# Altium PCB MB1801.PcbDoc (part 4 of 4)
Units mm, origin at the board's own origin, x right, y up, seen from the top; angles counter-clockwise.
Board outline 70.1 x 57.1 mm, 4 copper layers (Top Layer, Signal Layer 1, Signal Layer 2, Bottom Layer), stack 1.614 mm thick; 219 components, 166 nets, 1002 pads, 473 vias.
Unrouted connection lines stored in the file: 2.

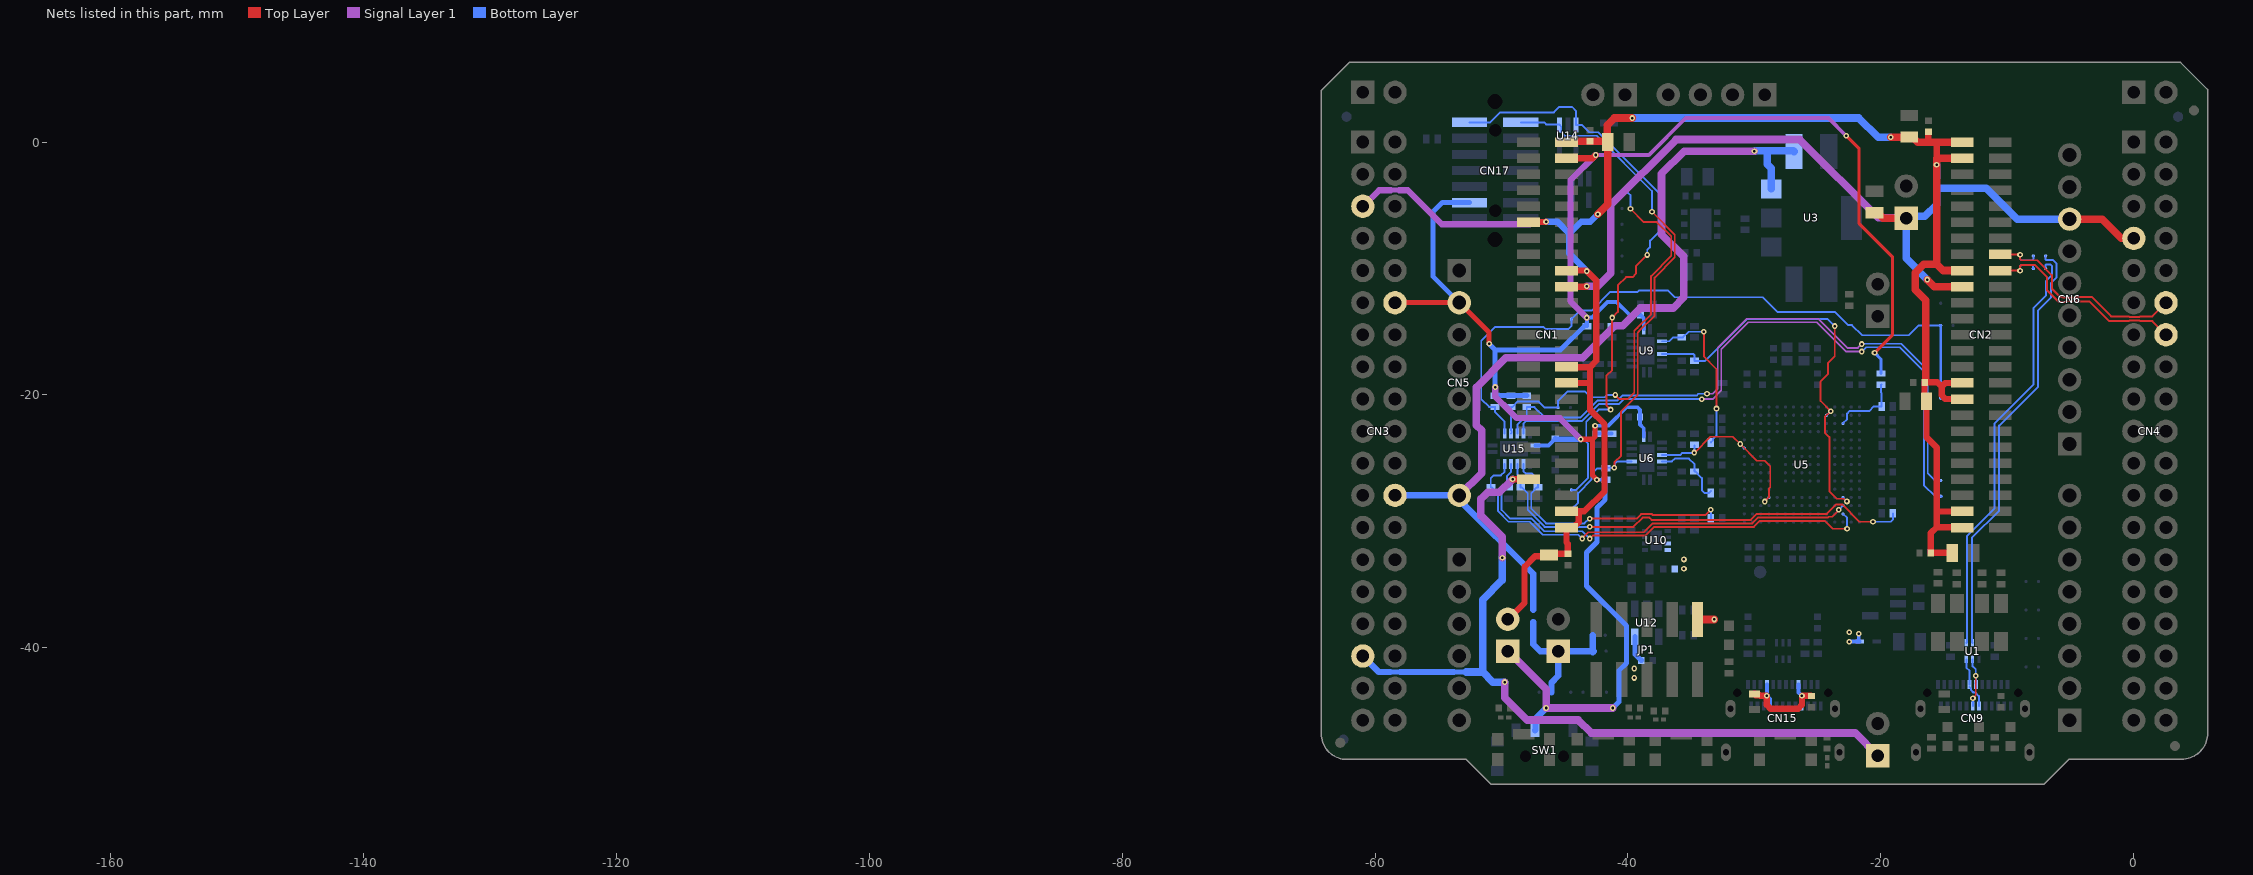
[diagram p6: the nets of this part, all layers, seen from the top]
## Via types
v1: diameter 0.45, hole 0.2, Top Layer to Bottom Layer, tented both sides, 473 vias

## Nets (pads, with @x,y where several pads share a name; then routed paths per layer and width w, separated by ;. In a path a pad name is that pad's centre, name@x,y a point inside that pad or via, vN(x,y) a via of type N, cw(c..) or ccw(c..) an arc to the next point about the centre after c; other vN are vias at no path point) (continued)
T_SWDIO: R26.1 U5.L2 U5.N12 U9.5 | length 32.6
  Top Layer w0.15: -24.1,-23.325 -24.425,-23 -24.425,-21.725 v1(-23.975,-21.275) -24.775,-20.475 -24.775,-18.925 -24.175,-18.325 -24.175,-17.45 -23.65,-16.925 v1(-23.65,-14.55) ; -24.075,-23.325 -24.075,-27.626 -23.501,-28.2 -22.921,-28.2 -22.705,-28.416 v1(-22.683,-28.416)
  Bottom Layer w0.15: U9.5@-37.3,-16.75 -34.85,-16.75 -34.75,-16.85 R26.1@-34.75,-17.3 -33.889,-17.3 -30.589,-14 -24.2,-14 v1(-23.65,-14.55) ; U5.L2@-24.3,-21.6 v1(-23.975,-21.275) ; U5.N12@-23,-28.1 v1(-22.683,-28.416)
T_SWO: R15.1 U5.A6 U5.D12 U6.4 | length 14.6
  Top Layer w0.15: v1(-34.75,-24.55) -34.725,-24.55 -33.475,-23.3 -31.7,-23.3 v1(-31.125,-23.875) -29.8,-25.2 -29.199,-25.2 -28.825,-25.574 ; v1(-29.175,-28.425) -28.85,-28.1 -28.85,-27.401 -28.825,-27.376 -28.75,-27.301 -28.75,-25.649 -28.825,-25.574
  Bottom Layer w0.15: U6.4@-37.3,-24.75 -35.875,-24.75 -35.7,-24.575 -34.75,-24.575 -34.75,-24.025 R15.1@-34.725,-24 ; v1(-31.125,-23.875) U5.A6@-30.8,-24.2 ; v1(-29.175,-28.425) U5.D12@-28.85,-28.1
T_VCC_AIN: R31.1 R33.1 U5.N3 | length 5.6
  Bottom Layer w0.15: U5.N3@-23,-22.25 -22.675,-21.925 -22.675,-21.467 -22.485,-21.277 -20.927,-21.277 -20.55,-20.9 R31.1@-20,-20.9 ; R31.1@-19.95,-20.9 -19.95,-19.928 -19.953,-19.925 -19.953,-19.847 -20,-19.8 R33.1@-20,-19.2 R33.1@-19.95,-19.15
T_VCP1_RX: R16.1 R55.2 U6.5 | length 6
  Bottom Layer w0.15: U6.5@-37.3,-25.25 -36.525,-25.25 -36.3,-25.025 -35.175,-25.025 -34.75,-25.45 -34.75,-25.5 -34.75,-25.925 R16.1@-34.775,-25.95 ; R16.1@-34.75,-26.05 -34.655,-26.05 -34.475,-26.23 -34.475,-26.25 -34.15,-26.575 -34.15,-27.525 -33.925,-27.75 -33.605,-27.75 R55.2@-33.45,-27.595
T_VCP1_TX: R24.2 R56.2 U9.3 | length 13
  Top Layer w0.15: v1(-34,-15) -34,-16.95 -33,-17.95 v1(-33,-21.075)
  Bottom Layer w0.15: U9.3@-37.3,-15.75 -36.725,-15.75 -36.425,-15.45 -35.655,-15.45 -35.205,-15 v1(-34,-15) ; R56.2@-33.45,-23.75 -33.27,-23.57 -33.27,-23.47 -33,-23.2 v1(-33,-21.075)
T_VCP2_CTS: R63.1 U5.N14 U15.5 | length 34.3
  Top Layer w0.15: v1(-43.025,-31.35) -43.012,-31.35 -42.787,-31.125 -38.636,-31.125 -37.936,-30.425 -30.047,-30.425 -29.572,-29.95 -24.425,-29.95 -23.8,-30.575 v1(-22.675,-30.575)
  Bottom Layer w0.15: R63.1@-49.595,-27.3 -49.775,-27.48 -50,-27.705 -50,-29.082 -49.332,-29.75 -47.653,-29.75 -46.628,-30.775 -43.6,-30.775 v1(-43.025,-31.35) ; R63.1@-49.57,-27.23 -49.57,-26.42 -49.25,-26.1 U15.5@-49.25,-25.45 ; U5.N14@-23,-29.4 -22.675,-29.725 v1(-22.675,-30.575)
T_VCP2_RTS: R64.1 U5.N13 U15.6 | length 34.1
  Top Layer w0.15: v1(-43.626,-31.351) -43.626,-31.337 -43.139,-30.85 -38.75,-30.85 -38.05,-30.15 -30.161,-30.15 -29.686,-29.675 -24.161,-29.675 -24.111,-29.625 -23.861,-29.625 v1@-23.305,-29.069
  Bottom Layer w0.15: U15.6@-49.75,-25.45 -49.75,-26.05 -50.05,-26.35 -50.6,-26.35 -50.85,-26.6 -50.85,-27.3 R64.1@-50.825,-27.3 -50.755,-27.3 -50.275,-27.78 -50.275,-29.196 -49.446,-30.025 -47.767,-30.025 -46.742,-31.05 -43.925,-31.05 v1(-43.626,-31.351) ; v1@-23.305,-29.069 -23.305,-29.055 U5.N13@-23,-28.75
  other v1: -23.325,-29.075
T_VCP2_RX: R57.2 R62.1 U15.4 | length 35.5
  Top Layer w0.15: v1(-43.025,-30.425) -39.575,-30.425 -38.849,-29.699 -38.3,-29.699 -38.124,-29.875 -30.275,-29.875 -29.8,-29.4 -24.275,-29.4 -23.525,-28.65 -23.075,-28.65 -21.7,-30.025 v1(-20.625,-30.025)
  Bottom Layer w0.15: U15.4@-48.75,-25.45 -48.75,-26.325 -48.5,-26.575 -48.5,-27.3 -48.38,-27.3 -48.2,-27.48 -48.2,-27.505 -47.925,-27.78 -47.925,-29.089 -46.589,-30.425 v1(-43.025,-30.425) ; v1(-20.625,-30.025) -19.225,-30.025 -19.05,-29.85 R57.2@-19.05,-29.35
T_VCP2_TX: R58.2 R61.1 U15.3 | length 20.4
  Top Layer w0.15: v1(-43.025,-29.775) -39.314,-29.775 -38.963,-29.424 -38.101,-29.424 -38.025,-29.5 -33.875,-29.5 v1(-33.45,-29.075)
  Bottom Layer w0.15: U15.3@-48.25,-25.45 -48.25,-26.05 -48.1,-26.2 -47.6,-26.2 -47.1,-26.7 R61.1@-47.1,-27.3 -47.195,-27.3 -47.65,-27.755 -47.65,-28.975 -46.475,-30.15 -43.438,-30.15 -43.063,-29.775 v1(-43.025,-29.775) ; R58.2@-33.45,-29.75 v1(-33.45,-29.075)
USB_C_N: CN9.A7 CN9.B7 U1.6 | length 4
  Bottom Layer w0.155: U1.6@-13.25,-40.9 -13.25,-41.55 -12.99,-41.81 CN9.A7@-12.99,-42.89 ; CN9.A7@-13,-43.08 -12.868,-43.212 -12.868,-43.334 -12.679,-43.522 -12.538,-43.522 -12.252,-43.808 -12.252,-44.578 CN9.B7@-12.24,-44.59
USB_C_P: CN9.A6 CN9.B6 U1.5 | length 4.5
  Top Layer w0.155: v1(-12.725,-43.975) -12.725,-43.962 -12.5,-43.737 v1(-12.5,-42.2)
  Bottom Layer w0.155: U1.5@-12.75,-40.9 -12.75,-41.45 -12.5,-41.7 v1(-12.5,-42.2) -12.495,-42.205 -12.495,-42.77 CN9.A6@-12.525,-42.8 ; CN9.B6@-12.74,-44.59 -12.732,-44.583 -12.732,-43.982 v1(-12.725,-43.975)
USB_FS_N: CN2.18 CN4.14 SB14.1 | length 18.1
  Top Layer w0.155: CN2.18@-10.565,-10.16 v1@-9,-10.16 ; v1(-9,-10.175) v1@-9,-10.16 ; CN4.14@2.54,-15.24 1.46,-14.16 0.515,-14.16 0.467,-14.112 -0.356,-14.112 -0.405,-14.16 -1.953,-14.16 -3.489,-12.625 -4.615,-12.625 -4.652,-12.588 -5.4,-12.588 -5.448,-12.636 -5.958,-12.636 -6.856,-11.738 -6.856,-10.683 -7.811,-9.728 -8.553,-9.728 -8.909,-9.728 -9,-9.819 v1@-9,-10.16
  Bottom Layer w0.155: v1(-9,-10.175) -9,-9.819 -8.909,-9.728 -8.042,-9.728 -7.967,-9.803 -7.967,-9.983 SB14.1@-7.95,-10
USB_FS_P: CN2.16 CN4.12 SB16.1 | length 18.2
  Top Layer w0.155: CN2.16@-10.565,-8.89 v1@-9,-8.89 ; v1(-9,-8.9) -9,-9.256 -8.909,-9.347 -8.711,-9.347 -7.653,-9.347 -6.475,-10.525 -6.475,-11.581 -5.8,-12.255 -5.627,-12.255 -5.579,-12.304 -4.675,-12.304 -4.615,-12.244 -3.331,-12.244 -1.795,-13.779 -0.405,-13.779 -0.356,-13.828 0.467,-13.828 0.515,-13.779 1.46,-13.779 CN4.12@2.54,-12.7
  Bottom Layer w0.155: v1(-9,-8.9) -9,-9.256 -8.909,-9.347 -8.041,-9.347 -7.95,-9.256 SB16.1@-7.95,-9
USB_N: SB14.2 U1.1 | length 33.5
  Bottom Layer w0.155: U1.1@-13.25,-39.6 -13.203,-39.552 -13.203,-39.299 -13.191,-39.287 -13.191,-31.141 -11.031,-28.981 -11.031,-22.256 -7.95,-19.175 -7.95,-13.144 -6.931,-12.125 -6.931,-10.981 -6.482,-10.532 -6.482,-9.781 -6.572,-9.691 -6.958,-9.691 -6.975,-9.708 SB14.2@-6.975,-10
USB_P: SB16.2 U1.2 | length 34.1
  Bottom Layer w0.155: U1.2@-12.75,-39.6 -12.798,-39.552 -12.798,-39.299 -12.81,-39.287 -12.81,-31.298 -10.65,-29.139 -10.65,-22.414 -7.569,-19.333 -7.569,-13.302 -6.55,-12.283 -6.55,-11.139 -6.101,-10.689 -6.101,-9.623 -6.415,-9.31 -6.958,-9.31 -6.975,-9.292 SB16.2@-6.975,-9
V_TARGET: C25.1 C31.1 C61.1 CN1.4 CN3.12 CN5.2 CN17.3 JP2.1 R18.2 R19.2 R28.2 R33.2 R60.2 R65.2 R66.2 R67.2 SB18.2 SW1.2 U6.16 U9.16 U15.16 | length 162
  Top Layer w0.25: v1(-22.75,0.5) -21.725,-0.525 -21.725,-6.45 -19.075,-9.1 -19.075,-15.225 v1(-20.5,-16.65)
  Top Layer w0.4: CN3.12@-58.42,-12.7 CN5.2@-53.34,-12.7 ; CN5.2@-53.25,-12.775 -50.975,-15.05 v1@-50.975,-15.936 ; v1(-43.725,-23.5) -42.8,-23.5 ; v1@-42.599,-22.439 -42.599,-23.299 -42.8,-23.5 ; v1(-42.45,-26.7) -42.8,-26.35 -42.8,-23.5
  Top Layer w0.5: CN1.4@-44.855,-1.27 -42.795,-1.27 v1(-42.55,-1.025)
  Signal Layer 1 w0.3: v1(-42.55,-1.025) -38.35,-1.025 -35.425,1.9 -24.15,1.9 v1(-22.75,0.5)
  Signal Layer 1 w0.5: v1(-50.5,-19.375) -50.5,-20.125 -49.9,-20.725 ; -49.875,-20.75 -48.8,-21.825 -45.4,-21.825 v1(-43.725,-23.5) ; v1@-43.263,-13.887 -44.55,-12.6 -44.55,-3.025 v1(-42.55,-1.025)
  Signal Layer 1 w0.6: JP2.1@-49.475,-40.275 -46.475,-43.275 v1(-46.475,-44.75) ; v1@-46.45,-44.725 -46.425,-44.75 v1(-41.2,-44.75)
  Bottom Layer w0.25: v1(-20.5,-16.65) -20,-17.15 R33.2@-20,-18.3
  Bottom Layer w0.3: U15.16@-47.3,-24 -46.275,-24 C61.1@-45.88,-23.605 ; R28.2@-43.25,-14.55 v1(-43.25,-13.875) -42.85,-13.875 -41.625,-12.65 -40.9,-12.65 -39.85,-13.7 C31.1@-39,-13.7 ; R18.2@-42.475,-23.025 -42.491,-23.025 -42.571,-22.945 -42.571,-22.454 -42.6,-22.425 -41.55,-22.425 -40.1,-20.975 -39.25,-20.975 -39.05,-21.175 C25.1@-39.05,-21.75 -39.05,-22.325 -38.75,-22.625 U6.16@-38.75,-23.3 ; v1(-42.45,-26.7) R19.2@-41.8,-26.7 ; R18.2@-42.45,-23.05 R60.2@-41.275,-23.05 ; C31.1@-39,-13.675 -38.75,-13.925 U9.16@-38.75,-14.8
  Bottom Layer w0.4: CN5.2@-53.34,-12.7 -55.4,-10.64 -55.4,-5.5 -54.675,-4.775 -52.547,-4.775 CN17.3@-52.532,-4.79 ; v1(-50.975,-15.95) -50.975,-15.964 -50.915,-16.024 -50.915,-16.035 -50.5,-16.45 ; R65.2@-48,-20.05 R66.2@-49.25,-20.05 R67.2@-50.5,-20.05 v1(-50.5,-19.375) -50.5,-16.45 ; C61.1@-45.75,-23.45 -45.7,-23.5 v1(-43.725,-23.5) ; R28.2@-43.375,-14.475 -45.35,-16.45 -50.5,-16.45 ; R19.2@-41.8,-26.7 -41.8,-28.275 -42.45,-28.925 -42.45,-31.625 -43.275,-32.45 -43.275,-35.1 -40.125,-38.25 -40.125,-41.2 -40.725,-41.8 SB18.2@-40.725,-43.5 ; v1(-41.2,-44.75) -40.725,-44.275 SB18.2@-40.725,-43.525
  Bottom Layer w0.5: SW1.2@-47.35,-46.509 -47.311,-46.471 -47.311,-45.586 v1(-46.475,-44.75)
  other v1: -42.599,-22.426
VBAT: CN1.43 CN3.33 CN14.1 | length 64.1
  Top Layer w0.5: v1(-49.125,-26.65) -47.875,-26.65 CN1.43@-47.855,-26.67
  Signal Layer 1 w0.6: v1(-49.925,-32.875) -49.925,-31.225 -51.625,-29.525 -51.625,-28.225 -51.1,-27.7 -50.175,-27.7 v1(-49.125,-26.65) ; v1(-49.75,-42.7) -49.75,-43.925 -47.975,-45.7 -43.925,-45.7 -42.9,-46.725 -22.045,-46.725 CN14.1@-20.25,-48.52
  Bottom Layer w0.4: -58.775,-41.9 -58.025,-41.9 ; -53.75,-41.9 -52.775,-41.9
  Bottom Layer w0.5: CN3.33@-60.96,-40.64 -59.7,-41.9 -58.775,-41.9 ; -58.025,-41.9 -57.125,-41.9 ; -57.1,-41.9 -53.75,-41.9
  Bottom Layer w0.6: -52.775,-41.9 -51.475,-41.9 ; v1(-49.925,-32.875) -49.925,-34.625 -51.475,-36.175 -51.475,-41.9 ; v1(-49.75,-42.7) -50.675,-42.7 -51.475,-41.9
VBUS_STLK: C23.1 C35.2 C58.2 CN15.A4 CN15.A9 CN15.B4 CN15.B9 D1.1 JP1.10 U7.1 U10.3 U10.4 U12.5 | length 14.7
  Top Layer w0.5: U7.1@-30.02,-43.625 -29.895,-43.75 -29.56,-43.75 -29.535,-43.775 v1(-29.02,-43.775) -29.02,-44.507 -28.727,-44.8 -26.538,-44.8 -26.245,-44.507 v1@-26.245,-43.8 ; v1(-26.245,-43.775) C23.1@-25.554,-43.775
  Top Layer w0.6: JP1.10@-34.5,-37.75 v1(-33.175,-37.75)
  Bottom Layer w0.3: CN15.A9@-29.01,-42.89 -29.01,-43.765 v1(-29.02,-43.775) -29.011,-43.775 -28.76,-44.026 CN15.B4@-28.76,-44.59 ; CN15.A4@-26.51,-42.89 -26.51,-43.522 -26.257,-43.775 v1(-26.245,-43.775) -26.26,-43.79 CN15.B9@-26.26,-44.59 ; v1(-22.5,-39.5) D1.1@-21.75,-39.5 ; v1(-21.75,-38.875) D1.1@-21.75,-39.5 ; D1.1@-21.675,-39.5 D1.1@-21.75,-39.5
  Bottom Layer w0.4: U12.5@-39.45,-39.1 -39.45,-40.5 -39.03,-40.92 -39.005,-40.92 -38.95,-40.975 C58.2@-38.95,-41
  other v1: -39.5,-42.375 -39.5,-41.625 -22.5,-38.75 -35.575,-33.75 -35.575,-33
VCP1_T_RX: CN17.13 R32.2 SB5.2 U14.3 | length 47.5
  Top Layer w0.15: v1(-41.376,-21.15) -41.7,-20.826 -41.7,-18.475 -41.25,-18.025 v1(-41.25,-13.875) -40.8,-13.425 -40.8,-11.325 -40.15,-10.675 -39.639,-10.675 -39.375,-10.411 -39.375,-9.828 v1@-38.475,-8.928
  Bottom Layer w0.15: CN17.13@-52.532,1.56 -50.89,1.56 -50.1,2.35 -45.85,2.35 -45.425,2.775 -44.425,2.775 -44.1,2.45 U14.3@-44.1,1.35 -43.65,1.35 -43.075,0.775 -42.361,0.775 -37.525,-4.061 -37.525,-7.075 -38.25,-7.8 -38.25,-8.3 -38.274,-8.324 -38.274,-8.326 -38.475,-8.528 v1(-38.475,-8.925) -38.469,-8.919 v1@-38.469,-8.9 ; SB5.2@-44.475,-27.5 -44.1,-27.5 -43.15,-26.55 -43.15,-23.85 -43.3,-23.7 -43.3,-22.125 -42.325,-21.15 v1(-41.376,-21.15) ; R32.2@-41.25,-14.55 v1(-41.25,-13.875)
VCP1_T_TX: CN17.14 R19.1 SB3.2 U6.12 U14.1 | length 44.9
  Top Layer w0.15: v1(-41.075,-25.75) -41.075,-25.325 -40.55,-24.8 -40.55,-21.3 -39.225,-19.975 -39.225,-15.063 -39.137,-14.975 ; -39.136,-14.975 -37.9,-13.739 -37.9,-10.715 -36.3,-9.115 -36.3,-8.903 -36.3,-7.325 -38.1,-5.525 v1(-38.1,-5.5)
  Bottom Layer w0.15: CN17.14@-48.468,1.56 -46.635,1.56 -46.475,1.4 -45.45,1.4 U14.1@-45.4,1.35 -45.275,1.225 -45.275,0.775 -45,0.5 -42.475,0.5 -38.1,-3.875 v1(-38.1,-5.5) ; SB3.2@-44.475,-29.25 -44.475,-29.05 -43.95,-28.525 -43.95,-27.75 -42.875,-26.675 -42.875,-26.25 -42.425,-25.8 R19.1@-41.75,-25.8 -41.7,-25.75 v1(-41.075,-25.75) -41.032,-25.707 -41.032,-25.432 -40.85,-25.25 U6.12@-39.7,-25.25
VCP2_T_CTS: R67.1 SB24.2 SB25.2 SB27.2 U15.11 | length 54.3
  Bottom Layer w0.15: U15.11@-49.75,-23.05 -49.75,-22.1 -50.5,-21.35 R67.1@-50.5,-20.95 -50.512,-20.938 -50.987,-20.938 -51.6,-20.325 -51.6,-15.7 -50.535,-14.635 -46.665,-14.635 -46.525,-14.775 -44.7,-14.775 -44.475,-14.55 SB27.2@-44.475,-14 -43.8,-13.325 -42.875,-13.325 -41.4,-11.85 -39.236,-11.85 -39.136,-11.75 -36.825,-11.75 -36.3,-12.275 -29.328,-12.275 -28.153,-13.45 -23.625,-13.45 -22.6,-14.475 -22.289,-14.475 -21.489,-15.275 -17.8,-15.275 -17.025,-14.5 SB24.2@-15.275,-14.5
  Bottom Layer w0.2: SB25.2@-15.275,-20.25 SB24.2@-15.275,-14.5
VCP2_T_RTS: R66.1 SB23.2 SB26.2 U15.12 | length 33.3
  Top Layer w0.15: v1(-41,-19.996) -41,-20 -40.675,-20.325 -40,-20.325 -39.5,-19.825 -39.5,-15.289 -39.5,-14.939 -39.256,-14.694 ; v1(-39.8,-5.275) -38.75,-6.325 -37.711,-6.325 -36.575,-7.461 -36.575,-8.789 -36.575,-9.001 -38.175,-10.601 -38.175,-13.625 -39.25,-14.7
  Bottom Layer w0.15: U15.12@-49.25,-23.05 -49.187,-22.987 -49.187,-22.863 -49.25,-22.8 R66.1@-49.25,-20.95 -49.155,-20.95 -48.705,-20.5 -47.075,-20.5 -46.575,-21 SB26.2@-45.525,-21 -45.525,-20.45 -44.8,-19.725 -43.389,-19.725 -42.939,-20.175 -41.835,-20.175 -41.825,-20.175 -41.646,-19.996 v1(-41,-19.996) ; SB23.2@-40.475,-4 -40,-4 -39.8,-4.2 v1(-39.8,-5.275)
VCP2_T_RX: SB7.2 U15.14 | length 50.4
  Signal Layer 1 w0.15: v1@-34.15,-20.35 -34.125,-20.325 -33.314,-20.325 -32.625,-19.636 -32.625,-16.389 -30.486,-14.25 -25.061,-14.25 -22.761,-16.55 -21.525,-16.55 v1(-21.512,-16.563)
  Bottom Layer w0.15: U15.14@-48.25,-23.05 -48.25,-22.25 -48.05,-22.05 -43.625,-22.05 -42.3,-20.725 -40.739,-20.725 -40.339,-20.325 -35.136,-20.325 v1(-34.175,-20.325) ; v1(-21.512,-16.563) -21.174,-16.225 -18.5,-16.225 -16.6,-18.125 -16.6,-27.125 -15.7,-28.025 -15.15,-28.025
VCP2_T_TX: R65.1 SB8.2 U15.13 | length 51
  Signal Layer 1 w0.15: v1(-33.75,-19.9) -33.278,-19.9 -32.9,-19.522 -32.9,-16.275 -30.6,-13.975 -24.947,-13.975 -22.647,-16.275 -21.825,-16.275 v1(-21.525,-15.975)
  Bottom Layer w0.15: U15.13@-48.75,-23.05 -48.75,-22.35 -48,-21.6 R65.1@-48,-20.95 -47.4,-20.95 -46.575,-21.775 -43.739,-21.775 -42.414,-20.45 -40.853,-20.45 -40.453,-20.05 -35.022,-20.05 -34.575,-20.05 -34.425,-19.9 v1(-33.75,-19.9) ; v1(-21.525,-15.975) -21.5,-15.95 -18.375,-15.95 -16.3,-18.025 -16.3,-26.2 -15.75,-26.75 SB8.2@-15.275,-26.75
VDD: C2.2 C3.2 C4.2 C5.2 C6.2 C7.2 C8.2 C9.2 C10.2 C11.2 CN1.2 CN1.11 CN1.18 CN1.30 CN1.32 CN1.48 CN1.50 CN2.1 CN2.3 CN2.17 CN2.31 CN2.33 CN2.47 CN2.49 CN3.5 JP2.2 SB1.1 | length 155
  Top Layer w0.5: JP2.2@-49.5,-37.75 -48.175,-36.425 -48.175,-33.575 -47.355,-32.755 -46.355,-32.755 C3.2@-46.25,-32.65 ; CN1.11@-47.855,-6.35 -47.83,-6.325 -46.5,-6.325 v1(-46.475,-6.3) ; C3.2@-46.225,-32.55 C8.2@-44.75,-32.55 -44.75,-31.75 -44.855,-31.645 CN1.50@-44.855,-30.48 -44.73,-30.355 -44.193,-30.355 -43.9,-30.062 -43.9,-29.225 ; CN1.32@-44.855,-19.05 -43,-19.05 ; CN1.18@-44.855,-10.16 -43.29,-10.16 -42.5,-10.95 -42.5,-17.3 -43,-17.8 ; CN1.30@-44.85,-17.8 -43,-17.8 ; -43.9,-29.2 -43.45,-29.2 -41.85,-27.6 -41.85,-22.325 -43,-21.175 -43,-19.05 ; -16.25,-0.025 C9.2@-16.25,0.8 ; -15.596,-1.27 -15.596,-0.025 -15.57,0 ; C6.2@-14.35,-32.475 -16.05,-32.475 -16.05,-30.909 -15.596,-30.455 ; CN2.49@-13.935,-30.48 -13.96,-30.455 -15.596,-30.455 ; CN2.47@-13.935,-29.21 -15.545,-29.21 -15.596,-29.261 ; CN2.33@-13.935,-20.32 -14.907,-20.32 -15.2,-20.027 -15.2,-19.343 ; CN2.31@-13.935,-19.05 -14.907,-19.05 -15.2,-19.343 ; -43,-19.05 -43,-17.8 ; -15.596,-30.455 -15.596,-29.261 ; -15.596,-29.261 -15.596,-24.154 -16.4,-23.35 C5.2@-16.4,-20.5 -16.55,-20.35 C10.2@-16.55,-19 -16.45,-19 -15.543,-19 -15.2,-19.343
  Top Layer w0.6: CN1.2@-44.855,0 -44.805,0.05 C7.2@-43,0.05 C2.2@-41.65,0.05 ; v1(-42.375,-5.7) -41.6,-4.925 C2.2@-41.6,0 C2.2@-41.65,0.05 ; v1(-39.65,1.9) -41.075,1.9 -41.65,1.325 C2.2@-41.65,0.05 ; v1(-19.225,0.375) C4.2@-17.775,0.375 ; C4.2@-17.725,0.375 -17.475,0.375 -17.075,-0.025 -16.25,-0.025 -15.596,-0.025 ; C10.2@-16.45,-19 -16.45,-12.525 -17.3,-11.675 -17.3,-10.325 -16.625,-9.65 -15.575,-9.65 ; -15.575,-1.275 -15.575,-9.65 ; -15.575,-1.27 CN2.3@-13.935,-1.27 ; -15.57,0 CN2.1@-13.565,0 ; CN2.17@-13.935,-10.16 -15.065,-10.16 -15.575,-9.65
  Signal Layer 1 w0.4: -58.75,-3.8 -58.075,-3.8
  Signal Layer 1 w0.5: CN3.5@-60.96,-5.08 -59.68,-3.8 -58.75,-3.8 ; -58.075,-3.8 -57.425,-3.8 -54.725,-6.5 -47.775,-6.5 -47.7,-6.425 -47.675,-6.425 -47.575,-6.325 v1@-46.525,-6.325
  Bottom Layer w0.5: v1(-46.475,-6.3) -45.575,-6.3 -44.638,-7.237 ; v1(-43.25,-10.2) -44.638,-8.812 -44.638,-7.237 ; v1(-42.375,-5.7) -42.975,-6.3 -43.701,-6.3 -44.638,-7.237
  Bottom Layer w0.6: v1(-39.65,1.9) -21.75,1.9 -20.225,0.375 v1(-19.225,0.375) ; v1(-15.6,-1.8) -15.6,-2.775 SB1.1@-15.575,-2.8
VDDA: C1.2 CN1.20 CN2.19 CN4.7 CN6.8 CN11.1 SB1.2 | length 69.2
  Top Layer w0.5: CN1.20@-44.879,-11.43 CN1.20@-44.855,-11.43 -43.28,-11.43 v1(-43.25,-11.4)
  Top Layer w0.6: C1.2@-20.5,-5.6 -20.25,-5.6 -19.83,-6.02 CN11.1@-18,-6.02 ; v1(-16.325,-10.875) -15.77,-11.43 CN2.19@-13.935,-11.43 ; CN6.8@-5.08,-6.096 -2.504,-6.096 -0.98,-7.62 CN4.7@0,-7.62
  Signal Layer 1 w0.6: v1(-43.25,-11.4) -42.4,-11.4 -41.375,-10.375 -41.375,-4.975 -36.2,0.2 -26.425,0.2 -20.225,-6 CN11.1@-17.95,-6
  Bottom Layer w0.6: v1(-16.325,-10.875) -18,-9.2 CN11.1@-18,-6.02 -17.856,-5.876 -16.526,-5.876 -15.6,-4.95 SB1.2@-15.6,-3.775 ; -15.25,-3.656 -11.669,-3.656 -9.229,-6.096 CN6.8@-5.08,-6.096
Vext: CN10.1 SB20.1 SB21.1 SB22.1 SB33.2 | length 11.6
  Bottom Layer w0.5: SB20.1@-47.5,-37.95 -47.5,-39.7 -46.93,-40.27 CN10.1@-45.5,-40.27 ; SB22.1@-46.05,-43.5 -46.05,-42.75 -45.5,-42.2 CN10.1@-45.5,-40.27 ; SB21.1@-42.775,-40.35 SB21.1@-42.725,-40.3 ; SB33.2@-42.775,-39 -42.775,-40.215 SB21.1@-42.72,-40.27 ; SB21.1@-42.7,-40.25 SB21.1@-42.72,-40.27 ; CN10.1@-45.5,-40.27 SB21.1@-42.72,-40.27
VIN: C16.1 C18.2 CN3.24 CN5.8 SB20.2 U3.3 | length 70.2
  Signal Layer 1 w0.6: CN5.8@-53.34,-27.94 -51.575,-26.175 -51.575,-22.8 -52,-22.375 -52,-21.2 -51.975,-21.175 -51.975,-19.375 -49.65,-17.05 -43.575,-17.05 -41.05,-14.525 -40.425,-14.525 -39.025,-13.125 -36.425,-13.125 -35.575,-12.275 -35.575,-9.05 -37.35,-7.275 -37.35,-2.525 -35.55,-0.725 v1(-30,-0.725)
  Bottom Layer w0.5: CN3.24@-58.42,-27.94 CN5.8@-53.34,-27.94 -53.34,-28.305 -47.5,-34.145 SB20.2@-47.5,-36.975
  Bottom Layer w0.6: v1@-29.975,-0.725 -29.95,-0.7 C18.2@-29,-0.7 ; U3.3@-28.675,-3.7 -28.675,-2.075 -29,-1.75 C18.2@-29,-0.7 ; C16.1@-26.875,-0.75 -26.925,-0.7 C18.2@-29,-0.7
pads on no net: 1.1 B1.5 B2.5 B3.5 B4.5 CN5.1 CN9.0 CN9.A2 CN9.A3 CN9.A8 CN9.A10 CN9.A11 CN9.B2 CN9.B3 CN9.B8 CN9.B10 CN9.B11 CN15.0 CN15.A2 CN15.A3 CN15.A8 CN15.A10 CN15.A11 CN15.B2 CN15.B3 CN15.B8 CN15.B10 CN15.B11 CN17.0 CN17.1 CN17.2 MIRE1.1 MIRE2.1 MIRE3.1 MIRE4.1 MIRE5.1 MIRE6.1 SW1.NPTH1 SW1.NPTH2 U1.4 U4.3 U4.5 U5.A1 U5.A2 U5.A3 U5.A4 U5.A5 U5.A8 U5.A9 U5.A11 U5.A12 U5.A13 U5.B1 U5.B4 U5.B5 U5.B6 U5.B7 U5.B8 U5.B9 U5.B10 U5.B11 U5.B12 U5.B15 U5.C2 U5.C3 U5.C4 U5.C12 U5.C13 U5.C14 U5.C15 U5.D1 U5.D2 U5.D3 U5.D11 U5.D13 U5.D14 U5.E1 U5.E2 U5.E3 U5.E4 U5.E12 U5.E13 U5.E14 U5.E15 U5.F1 U5.F4 U5.F14 U5.G4 U5.G14 U5.G15 U5.H2 U5.H3 U5.H4 U5.H14 U5.J2 U5.J3 U5.J4 U5.K1 U5.K2 U5.K3 U5.K12 U5.K13 U5.K14 U5.K15 U5.L1 U5.L12 U5.L13 U5.L14 U5.L15 U5.M2 U5.M3 U5.M4 U5.M7 U5.M12 U5.M13 U5.M14 U5.M15 U5.N2 U5.N4 U5.N6 U5.N7 U5.N11 U5.N15 U5.P2 U5.P4 U5.P5 U5.P6 U5.P7 U5.P8 U5.P9 U5.P10 U5.P11 U5.P12 U5.P13 U5.P14 U5.P15 U5.R2 U5.R6 U5.R7 U5.R8 U5.R9 U5.R10 U5.R11 U5.R12 U8.4 U11.4 U14.4

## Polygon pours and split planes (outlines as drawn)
GND on Bottom Layer "GND_L04_P012" (solid, remove dead copper, pour order 12): -65.405,7.671 6.706,7.671 6.706,-51.867 -65.405,-51.867
5V_STLK on Bottom Layer "VDDIO1_4_L01_P-001" (solid, remove dead copper, pour order 10): -38.45,-31.625 -38.45,-32.575 -39.45,-33.575 -39.45,-37.5 -40.875,-37.5 -42,-36.375 -42,-34.5 -41.125,-33.625 -41.125,-33.125 -41,-33 -40.5,-33 -40.125,-32.625 -40.125,-32.125 -39.625,-31.625
VBUS_STLK on Bottom Layer "VDDIO1_4_L01_P-001" (solid, remove dead copper, pour order 7): -39.75,-38.625 -39.75,-42.5 -39.5,-42.75 -38.875,-42.75 -38.75,-42.625 -38.75,-39.125 -39.25,-38.625
VBUS_STLK on Bottom Layer "VDDIO1_4_L01_P-001" (solid, remove dead copper, pour order 11): -37.05,-31.625 -35.75,-31.625 -35.25,-32.125 -35.25,-33.875 -35.375,-34 -36.5,-34 -36.5,-33.25 -37.05,-32.7 -37.05,-32.325
NetC54_2 on Bottom Layer "VDDIO1_4_L01_P-001" (solid, remove dead copper, pour order 5): -20.5,-39.75 -20.25,-40 -18.25,-40 -18.25,-37.25 -19.5,-37.25 -20,-37.75 -20,-38.5 -20.5,-39
VBUS_STLK on Bottom Layer "VDDIO1_4_L01_P-001" (solid, remove dead copper, pour order 4): -21.5,-39.5 -21.75,-39.75 -22.75,-39.75 -23,-39.5 -23,-38.5 -22.75,-38.25 -21.75,-38.25 -21.5,-38.5
3V3_STLK on Bottom Layer "VDDIO1_4_L01_P-001" (solid, remove dead copper, pour order 6): -19.25,-35.75 -19.25,-34.5 -19,-34.25 -16.5,-34.25 -16.5,-35 -17,-35.5 -17.25,-35.5 -17.5,-35.75
GND on Signal Layer 1 "VDDIO1_4_L01_P-001" (solid, remove dead copper, pour order 14): -64,-51.5 -64.5,-51 -64.5,4.5 -62.5,6.5 4,6.5 6,4.5 6,-50.5 5,-51.5
VBUS_STLK on Signal Layer 1 "VDDIO1_4_L01_P-001" (solid, remove dead copper, pour order 8): -36,-37 -36,-34 -36,-32.75 -31.25,-32.75 -26.5,-37.5 -22,-37.5 -21.5,-38 -21.5,-43 -23.25,-44.75 -30.75,-44.75 -32,-43.5 -39,-43.5 -40,-42.5 -40,-41
3V3_STLK on Signal Layer 1 "VDDIO1_4_L01_P-001" (solid, remove dead copper, pour order 13): -30.75,-32.5 -27.75,-35.5 -17.25,-35.5 -16.75,-35 -16.75,-32.75 -18.75,-30.75 -18.75,-12.75 -19.25,-12.25 -38,-12.25 -51.25,-25.5 -51.25,-29.5 -44.75,-29.5 -41.75,-32.5
GND on Signal Layer 2 "VDDIO1_4_L01_P-001" (solid, remove dead copper, pour order 9): -64.5,-51 -64.5,6.5 6,6.5 6,-51
GND on Top Layer "GND_L01_P002" (solid, remove dead copper, pour order 2): -65.253,7.747 6.731,7.747 6.731,-51.791 -65.253,-51.791

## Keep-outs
Keep-Out Layer:
  lines w0.1: 3.781,-48.75 ccw(c3.794,-46.744) 5.8,-46.757 ; 3.794,-48.75 -5.15,-48.75 -7.15,-50.75 -50.775,-50.75 -52.775,-48.75 -62.2,-48.75 cw(c-62.263,-46.812) -64.2,-46.875 -64.2,4.075 -62,6.275 3.65,6.275 5.8,4.125 5.8,-46.744

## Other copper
Top Layer:
  text "1" at -60,-48.5 h2
Signal Layer 1:
  text "2" at -58.75,-48.5 h2
Signal Layer 2:
  text "3" at -56.25,-48.5 h2
Bottom Layer:
  pour cut-out: -23.65,-21.15 -24,-21.5 -32.375,-21.5 -32.9,-22.025 -32.9,-30.9 -25.675,-30.9 -24.225,-29.45 -24.225,-27.625 -28.375,-27.625 -28.375,-23.375 -24.102,-23.375 -24.15,-28.275 -24.15,-29.75 -24.138,-29.762 -24.138,-30.288 -23.225,-31.2 -23.2,-31.2 -22.75,-31.65 -22.75,-33.125 -22.575,-33.3 -21.75,-32.475 -21.75,-30.375 -21.6,-30.225 -20.25,-30.225 -20.25,-21.15
  text "4" at -54.75,-48.5 h2
Multi-Layer:
  pour cut-out: -60.625,-46.75 -60.625,-49 -54.25,-49 -54.25,-46.75

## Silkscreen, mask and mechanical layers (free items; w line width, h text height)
Top Overlay:
  text "GND" at -0.1,5.4 h1.3
  text "GND" at -60.8,5.375 h1.3
  text "J" at -10.6,1.95 h7.62
  text "2" at 3.96,-0.533 h1.5
  text "1" at -63.05,-0.584 h1.5
  text "2" at -56.9,-0.634 h1.5
  text "1" at -2.025,-0.622 h1.5
  text "10" at -7.864,-1.651 h1.5
  text "4" at 3.96,-3.15 h1.5
  text "3" at -63.1,-3.175 h1.5
  text "4" at -56.9,-3.2 h1.5
  text "3" at -2.25,-3.226 h1.5
  text "9" at -7.186,-4.191 h1.5
  text "MB1801D" at -52.222,-4.445 h2.5 r90
  text "6" at 3.96,-5.613 h1.5
  text "5" at -63.094,-5.715 h1.5
  text "6" at -56.9,-5.739 h1.5
  text "5" at -2.296,-5.829 h1.5
  text "8" at -7.186,-6.655 h1.5
  text "8" at 3.96,-8.103 h1.5
  text "8" at -56.9,-8.227 h1.5
  text "7" at -63.094,-8.255 h1.5
  text "7" at -2.296,-8.268 h1.5
  text "7" at -7.2,-9.373 h1.5
  text "10" at 3.96,-10.693 h1.5
  text "9" at -63.094,-10.744 h1.5
  text "9" at -2.296,-10.782 h1.5
  text "10" at -56.9,-10.945 h1.5
  text "H" at -36.001,-11.2 h7.62
  text "C" at -30.251,-11.2 h7.62
  text "6" at -7.186,-11.887 h1.5
  text "12" at 3.96,-13.208 h1.5
  text "12" at -56.9,-13.3 h1.5
  text "2" at -52,-13.3 h1.5
  text "11" at -2.702,-13.297 h1.5
  text "11" at -63.75,-13.35 h1.5
  text "5" at -7.186,-14.326 h1.5
  text "3" at -51.996,-15.748 h1.5
  text "14" at 3.96,-15.799 h1.5
  text "14" at -56.9,-15.902 h1.5
  text "13" at -63.771,-15.926 h1.5
  text "13" at -2.723,-15.989 h1.5
  text "4" at -7.186,-16.789 h1.5
  text "E" at -30.051,-17.6 h7.62
  text "I" at -35.35,-17.7 h7.62
  text "16" at 3.96,-18.364 h1.5
  text "15" at -63.771,-18.39 h1.5
  text "4" at -52,-18.4 h1.5
  text "16" at -56.9,-18.459 h1.5
  text "15" at -2.723,-18.504 h1.5
  text "3" at -7.186,-19.304 h1.5
  text "18" at 3.96,-20.955 h1.5
  text "18" at -56.9,-20.966 h1.5
  text "17" at -63.771,-21.006 h1.5
  text "5" at -52,-21 h1.5
  text "17" at -2.723,-21.095 h1.5
  text "2" at -7.186,-21.971 h1.5
  text "6" at -52,-23.35 h1.5
  text "19" at -63.771,-23.457 h1.5
  text "19" at -2.723,-23.482 h1.5
  text "20" at 3.96,-23.635 h1.5
  text "20" at -56.9,-23.709 h1.5
  text "7" at -51.95,-25.9 h1.5
  text "21" at -63.771,-25.959 h1.5
  text "21" at -2.723,-26.048 h1.5
  text "22" at 3.96,-26.099 h1.5
  text "22" at -56.9,-26.172 h1.5
  text "8" at -51.95,-28.45 h1.5
  text "23" at -63.906,-28.512 h1.5
  text "8" at -7.214,-28.55 h1.5
  text "23" at -2.859,-28.537 h1.5
  text "24" at 3.96,-28.613 h1.5
  text "24" at -56.9,-28.687 h1.5
  text "25" at -63.906,-31.052 h1.5
  text "25" at -2.859,-31.077 h1.5
  text "7" at -7.214,-31.14 h1.5
  text "26" at 3.96,-31.179 h1.5
  text "26" at -56.9,-31.252 h1.5
  text "6" at -7.214,-33.553 h1.5
  text "28" at 3.96,-33.566 h1.5
  text "27" at -63.906,-33.604 h1.5
  text "27" at -2.859,-33.592 h1.5
  text "28" at -56.9,-33.64 h1.5
  text "29" at -63.906,-36.055 h1.5
  text "5V_STLK" at -41.75,-36.05 h1.5 r90
  text "5V_USB" at -39.7,-36.05 h1.5 r90
  text "5V_INT" at -37.75,-36.05 h1.5 r90
  text "VEXT" at -36,-36.05 h1.5 r90
  text "VBUS_STLK" at -33.75,-36.05 h1.5 r90
  text "2" at -52.019,-36.093 h1.5
  text "29" at -2.859,-36.081 h1.5
  text "5" at -7.214,-36.22 h1.5
  text "30" at 3.96,-36.233 h1.5
  text "30" at -56.9,-36.307 h1.5
  text "31" at -63.906,-38.684 h1.5
  text "3" at -52.019,-38.735 h1.5
  text "32" at 3.96,-38.722 h1.5
  text "31" at -2.859,-38.748 h1.5
  text "4" at -7.214,-38.786 h1.5
  text "32" at -56.9,-38.796 h1.5
  text "L" at -28.9,-38.8 h14.25
  text "33" at -63.906,-41.135 h1.5
  text "4" at -52.019,-41.148 h1.5
  text "3" at -7.214,-41.148 h1.5
  text "33" at -2.859,-41.161 h1.5
  text "34" at 3.96,-41.364 h1.5
  text "34" at -56.9,-41.438 h1.5
  text "PWR" at -16.5,-41.5 h1.5
  text "COM" at -12.75,-41.5 h1.5
  text "5" at -52.019,-43.6 h1.5
  text "35" at -63.906,-43.726 h1.5
  text "35" at -2.859,-43.752 h1.5
  text "36" at 3.96,-43.752 h1.5
  text "2" at -7.214,-43.79 h1.5
  text "36" at -56.9,-43.825 h1.5
  text "6" at -52.019,-46 h1.5
  text "RESET" at -29.7,-46.2 h1.5
  text "38" at 3.96,-46.215 h1.5
  text "37" at -63.85,-46.25 h1.5
  text "38" at -56.9,-46.289 h1.5
  text "37" at -2.859,-46.393 h1.5
Bottom Overlay:
  lines w0.12: -34,-27 -34,-21.35 -32,-21.35 -32,-27 ; -33.95,-11.25 -33.95,-17.3 -33.7,-17.55 -31.65,-17.55 -31.35,-17.25 -31.35,-11.25 ; -33.125,-21.35 -33.125,-17.55 ; -22.7,-50.25 -22.7,-45.15 -21.35,-45.15 -21.35,-50.25 -22.7,-50.25 ; -19.15,-50.25 -17.8,-50.25 -17.8,-46.1 -19.15,-46.1 -19.15,-50.25
  lines w0.5: -43.33,-46.224 -41.197,-46.224 ; -41.933,-45.894 -41.197,-46.224 ; -41.908,-46.58 -41.197,-46.224
  text "GND" at -58.35,5.1 h1.5
  text "GND" at 2.75,5.05 h1.5
  text "1" at -62.23,-0.483 h1.5
  text "1" at -1.243,-0.559 h1.5
  text "2" at -56.375,-0.612 h1.5
  text "2" at 4.512,-0.673 h1.5
  text "10" at -6.25,-1.55 h1.5
  text "3" at -1.243,-2.934 h1.5
  text "3" at -62.23,-3.023 h1.5
  text "4" at -56.375,-3.05 h1.5
  text "4" at 4.512,-3.112 h1.5
  text "5" at -1.243,-5.601 h1.5
  text "6" at -56.375,-5.641 h1.5
  text "5" at -62.23,-5.69 h1.5
  text "6" at 4.512,-5.702 h1.5
  text "8" at -56.375,-8.054 h1.5
  text "7" at -1.243,-8.039 h1.5
  text "7" at -62.23,-8.128 h1.5
  text "8" at 4.512,-8.115 h1.5
  text "9" at -1.243,-10.554 h1.5
  text "9" at -62.23,-10.643 h1.5
  text "1" at -51.816,-10.744 h1.5
  text "10" at 5.011,-10.809 h1.5
  text "10" at -55.825,-10.947 h1.5
  text "11" at -1.243,-13.068 h1.5
  text "11" at -62.23,-13.157 h1.5
  text "12" at 5.011,-13.171 h1.5
  text "12" at -55.825,-13.31 h1.5
  text "13" at -1.243,-15.761 h1.5
  text "14" at 5.011,-15.76 h1.5
  text "14" at -55.825,-15.799 h1.5
  text "13" at -62.23,-15.85 h1.5
  text "16" at 5.011,-18.224 h1.5
  text "16" at -55.825,-18.263 h1.5
  text "15" at -1.243,-18.275 h1.5
  text "15" at -62.23,-18.364 h1.5
  text "18" at 5.011,-20.84 h1.5
  text "18" at -55.825,-20.879 h1.5
  text "17" at -1.243,-20.866 h1.5
  text "17" at -62.23,-20.955 h1.5
  text "19" at -1.243,-23.254 h1.5
  text "19" at -62.23,-23.343 h1.5
  text "20" at -55.775,-23.47 h1.5
  text "20" at 5.061,-23.582 h1.5
  text "1" at -6.38,-24.509 h1.5
  text "21" at -1.243,-25.819 h1.5
  text "21" at -62.23,-25.908 h1.5
  text "22" at -55.775,-25.934 h1.5
  text "22" at 5.061,-26.045 h1.5
  text "23" at -1.243,-28.308 h1.5
  text "23" at -62.23,-28.397 h1.5
  text "8" at -6.3,-28.4 h1.5
  text "24" at -55.775,-28.449 h1.5
  text "8" at -51.46,-28.524 h1.5
  text "24" at 5.061,-28.56 h1.5
  text "25" at -1.243,-30.848 h1.5
  text "25" at -62.23,-30.937 h1.5
  text "26" at -55.775,-31.014 h1.5
  text "26" at 5.061,-31.125 h1.5
  text "27" at -1.243,-33.363 h1.5
  text "28" at -55.775,-33.402 h1.5
  text "27" at -62.23,-33.452 h1.5
  text "1" at -51.816,-33.503 h1.5
  text "28" at 5.061,-33.513 h1.5
  text "29" at -1.243,-35.852 h1.5
  text "29" at -62.23,-35.941 h1.5
  text "30" at -55.775,-36.069 h1.5
  text "30" at 5.061,-36.18 h1.5
  text "31" at -1.243,-38.519 h1.5
  text "32" at -55.775,-38.558 h1.5
  text "31" at -62.23,-38.608 h1.5
  text "32" at 5.061,-38.669 h1.5
  text "33" at -1.243,-40.932 h1.5
  text "33" at -62.23,-41.021 h1.5
  text "34" at -55.775,-41.2 h1.5
  text "34" at 5.061,-41.311 h1.5
  text "35" at -1.243,-43.523 h1.5
  text "36" at -55.775,-43.587 h1.5
  text "35" at -62.23,-43.612 h1.5
  text "36" at 5.061,-43.698 h1.5
  text "default" at -42.75,-45.65 h1.5
  text "38" at -55.775,-46.051 h1.5
  text "37" at -1.396,-46.165 h1.5
  text "38" at 5.061,-46.162 h1.5
  text "37" at -62.23,-46.253 h1.5
  text "6" at -51.486,-46.304 h1.5
  text "1" at -4.75,-47.75 h1.5
  text "STLINK" at -22.55,-50 h1.5 r270
  text "USER" at -18.95,-50 h1.5 r270
Top Solder:
  rectangle: -60.375,-48.75 -54.5,-47
Bottom Solder:
  rectangle: -60.375,-48.75 -54.5,-47
M1-Board Shape:
  lines w0.1: -62.21,-48.768 cw(c-62.21,-46.768) -64.21,-46.768 -64.21,1.271 -64.21,4.048 -62.001,6.257 3.658,6.257 5.79,4.125 5.79,2.211 5.79,-46.743 cw(c3.79,-46.743) 3.79,-48.743 -5.131,-48.743 -7.131,-50.743 -50.786,-50.743 -52.761,-48.768 ; -62.21,-48.76 -52.789,-48.76
Drill Drawing:
  drawing of 293 lines, arcs and shapes, not listed
  text "PCB : TYPE 3" at -32.339,107.553 h3
  text "ASPECT-RATIO, AXE Z :" at -32.339,102.053 h3
  text "6:1 to 8:1 / LEVEL \"B\"" at -32.32,95.305 h3
  text "MINIMUM PARAMETERS" at -32.095,86.18 h3
  text "DEFAULT" at -32.095,80.68 h3
  text "TRACKS : 0.150mm           / GAPS : 0.120mm" at -32.095,74.93 h3
  text "Symbol" at -179.284,64.581 h2.16
  text "Count" at -170.822,64.581 h2.16
  text "Hole Size" at -162.037,64.581 h2.16
  text "Plated" at -146.487,64.581 h2.16
  text "Hole Type" at -139.059,64.581 h2.16
  text "Drill Layer Pair" at -128.244,64.581 h2.16
  text "Via/Pad" at -107.745,64.581 h2.16
  text "Pad Shape" at -98.884,64.581 h2.16
  text "Template" at -87.308,64.581 h2.16
  text "Description" at -74.592,64.581 h2.16
  text "Hole Tolerance (+)" at -62.965,64.581 h2.16
  text "Hole Tolerance (-)" at -44.887,64.581 h2.16
  text "Hole Length" at -27.294,64.581 h2.16
  text "Routed Path Length" at -11.743,64.581 h2.16
  text "2" at -170.822,60.853 h1.8
  text "0.65mm (25.59mil)" at -162.037,60.853 h1.8
  text "NPTH" at -146.487,60.853 h1.8
  text "Round" at -139.059,60.853 h1.8
  text "Top Layer - Bottom Layer" at -128.244,60.853 h1.8
  text "Pad" at -107.745,60.853 h1.8
  text "Rounded" at -98.884,60.853 h1.8
  text "c0hn65m5" at -87.308,60.853 h1.8
  text "-" at -27.294,60.853 h1.8
  text "-" at -11.743,60.853 h1.8
  text "2" at -170.822,57.125 h1.8
  text "0.65mm (25.59mil)" at -162.037,57.125 h1.8
  text "NPTH" at -146.487,57.125 h1.8
  text "Slot" at -139.059,57.125 h1.8
  text "Top Layer - Bottom Layer" at -128.244,57.125 h1.8
  text "Pad" at -107.745,57.125 h1.8
  text "Rounded" at -98.884,57.125 h1.8
  text "c0hn65_95m5" at -87.308,57.125 h1.8
  text "0.95mm (37.40mil)" at -27.294,57.125 h1.8
  text "0.30mm (11.81mil)" at -11.743,57.125 h1.8
  text "2" at -170.822,53.397 h1.8
  text "0.90mm (35.43mil)" at -162.037,53.397 h1.8
  text "NPTH" at -146.487,53.397 h1.8
  text "Round" at -139.059,53.397 h1.8
  text "Top Layer - Bottom Layer" at -128.244,53.397 h1.8
  text "Pad" at -107.745,53.397 h1.8
  text "Rounded" at -98.884,53.397 h1.8
  text "c0hn90m95" at -87.308,53.397 h1.8
  text "-" at -27.294,53.397 h1.8
  text "-" at -11.743,53.397 h1.8
  text "2" at -170.822,49.669 h1.8
  text "0.97mm (38.19mil)" at -162.037,49.669 h1.8
  text "NPTH" at -146.487,49.669 h1.8
  text "Round" at -139.059,49.669 h1.8
  text "Top Layer - Bottom Layer" at -128.244,49.669 h1.8
  text "Pad" at -107.745,49.669 h1.8
  text "Rounded" at -98.884,49.669 h1.8
  text "c0hn97m102" at -87.308,49.669 h1.8
  text "-" at -27.294,49.669 h1.8
  text "-" at -11.743,49.669 h1.8
  text "2" at -170.822,45.94 h1.8
  text "1.19mm (46.85mil)" at -162.037,45.94 h1.8
  text "NPTH" at -146.487,45.94 h1.8
  text "Round" at -139.059,45.94 h1.8
  text "Top Layer - Bottom Layer" at -128.244,45.94 h1.8
  text "Pad" at -107.745,45.94 h1.8
  text "Rounded" at -98.884,45.94 h1.8
  text "c0hn119m124" at -87.308,45.94 h1.8
  text "-" at -27.294,45.94 h1.8
  text "-" at -11.743,45.94 h1.8
  text "8" at -170.822,42.212 h1.8
  text "0.50mm (19.69mil)" at -162.037,42.212 h1.8
  text "PTH" at -146.487,42.212 h1.8
  text "Slot" at -139.059,42.212 h1.8
  text "Top Layer - Bottom Layer" at -128.244,42.212 h1.8
  text "Pad" at -107.745,42.212 h1.8
  text "Rounded" at -98.884,42.212 h1.8
  text "(Mixed)" at -87.308,42.212 h1.8
  text "1.10mm (43.31mil)" at -27.294,42.212 h1.8
  text "0.60mm (23.62mil)" at -11.743,42.212 h1.8
  text "32" at -170.822,38.484 h1.8
  text "1.10mm (43.31mil)" at -162.037,38.484 h1.8
  text "PTH" at -146.487,38.484 h1.8
  text "Round" at -139.059,38.484 h1.8
  text "Top Layer - Bottom Layer" at -128.244,38.484 h1.8
  text "Pad" at -107.745,38.484 h1.8
  text "Rounded" at -98.884,38.484 h1.8
  text "(Mixed)" at -87.308,38.484 h1.8
  text "-" at -27.294,38.484 h1.8
  text "-" at -11.743,38.484 h1.8
  text "96" at -170.822,34.756 h1.8
  text "1.00mm (39.37mil)" at -162.037,34.756 h1.8
  text "PTH" at -146.487,34.756 h1.8
  text "Round" at -139.059,34.756 h1.8
  text "Top Layer - Bottom Layer" at -128.244,34.756 h1.8
  text "Pad" at -107.745,34.756 h1.8
  text "Rounded" at -98.884,34.756 h1.8
  text "(Mixed)" at -87.308,34.756 h1.8
  text "-" at -27.294,34.756 h1.8
  text "-" at -11.743,34.756 h1.8
  text "473" at -170.822,31.027 h1.8
  text "0.20mm (7.87mil)" at -162.037,31.027 h1.8
  text "PTH" at -146.487,31.027 h1.8
  text "Round" at -139.059,31.027 h1.8
  text "Top Layer - Bottom Layer" at -128.244,31.027 h1.8
  text "Via" at -107.745,31.027 h1.8
  text "Rounded" at -98.884,31.027 h1.8
  text "v45h20m0mx0" at -87.308,31.027 h1.8
  text "-" at -27.294,31.027 h1.8
  text "-" at -11.743,31.027 h1.8
  text "619 Total" at -170.822,27.299 h1.8
  text "Slot definitions :" at -179.284,24.69 h1.8
  text "Routed Path Length" at -166.999,24.69 h1.8
  text "= Calculated from tool start centre position to tool end centre position." at -151.779,24.69 h1.8
  text "Hole Length" at -166.999,23.198 h1.8
  text "= Routed Path Length + Tool Size = Slot length as defined in the PCB layout" at -157.429,23.198 h1.8
  text "Layer" at -178.067,13.983 h1.52
  text "Name" at -171.689,13.983 h1.52
  text "Material" at -159.355,13.983 h1.52
  text "Thickness" at -148.272,13.983 h1.52
  text "Constant" at -139.168,13.983 h1.52
  text "Board Layer Stack" at -130.742,13.983 h1.52
  text "Top Overlay" at -171.689,10.935 h1.52
  text "Top Solder" at -171.689,7.887 h1.52
  text "Solder Resist" at -159.355,7.887 h1.52
  text "0.015mm" at -148.272,7.887 h1.52
  text "3.5" at -139.168,7.887 h1.52
  text "1" at -178.067,4.839 h1.52
  text "Top Layer" at -171.689,4.839 h1.52
  text "0.042mm" at -148.272,4.839 h1.52
  text "Dielectric 1" at -171.689,1.791 h1.52
  text "PP-IT-180A" at -159.355,1.791 h1.52
  text "0.106mm" at -148.272,1.791 h1.52
  text "4.2" at -139.168,1.791 h1.52
  text "2" at -178.068,-1.257 h1.52
  text "Signal Layer 1" at -171.689,-1.257 h1.52
  text "0.035mm" at -148.272,-1.257 h1.52
  text "Dielectric 2" at -171.689,-4.305 h1.52
  text "FR-4" at -159.355,-4.305 h1.52
  text "1.248mm" at -148.272,-4.305 h1.52
  text "4.2" at -139.168,-4.305 h1.52
  text "3" at -178.067,-7.353 h1.52
  text "Signal Layer 2" at -171.689,-7.353 h1.52
  text "0.035mm" at -148.272,-7.353 h1.52
  text "Dielectric 3" at -171.689,-10.401 h1.52
  text "PP-IT-180A" at -159.355,-10.401 h1.52
  text "0.106mm" at -148.272,-10.401 h1.52
  text "4.2" at -139.168,-10.401 h1.52
  text "4" at -178.067,-13.449 h1.52
  text "Bottom Layer" at -171.689,-13.449 h1.52
  text "0.042mm" at -148.272,-13.449 h1.52
  text "Bottom Solder" at -171.689,-16.497 h1.52
  text "Solder Resist" at -159.355,-16.497 h1.52
  text "0.015mm" at -148.272,-16.497 h1.52
  text "3.5" at -139.168,-16.497 h1.52
  text "Bottom Overlay" at -171.689,-19.545 h1.52

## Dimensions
-62.21,-48.76 to -60.96,-45.72 on M3-Top Dimensions
-64.21,-46.768 to 5.79,-46.743 on M2-Board Dimensions
-7.131,-50.743 to 3.658,6.257 on M2-Board Dimensions
-7.131,-50.743 to -5.131,-48.743 on M2-Board Dimensions
-5.11,-48.793 to 5.79,-46.743 on M2-Board Dimensions
-7.131,-50.743 to -50.786,-50.743 on M2-Board Dimensions
-50.786,-50.743 to -52.789,-48.76 on M2-Board Dimensions
-52.79,-48.81 to -64.21,-46.768 on M2-Board Dimensions
-7.131,-50.743 to -5.131,-48.743 on M2-Board Dimensions
3.79,-48.743 to 3.658,6.257 on M2-Board Dimensions
5.79,4.125 to 3.658,6.257 on M2-Board Dimensions
-46.345,-15.24 to -12.055,-15.24 on M3-Top Dimensions
-48.225,0 to -13.935,0 on M3-Top Dimensions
